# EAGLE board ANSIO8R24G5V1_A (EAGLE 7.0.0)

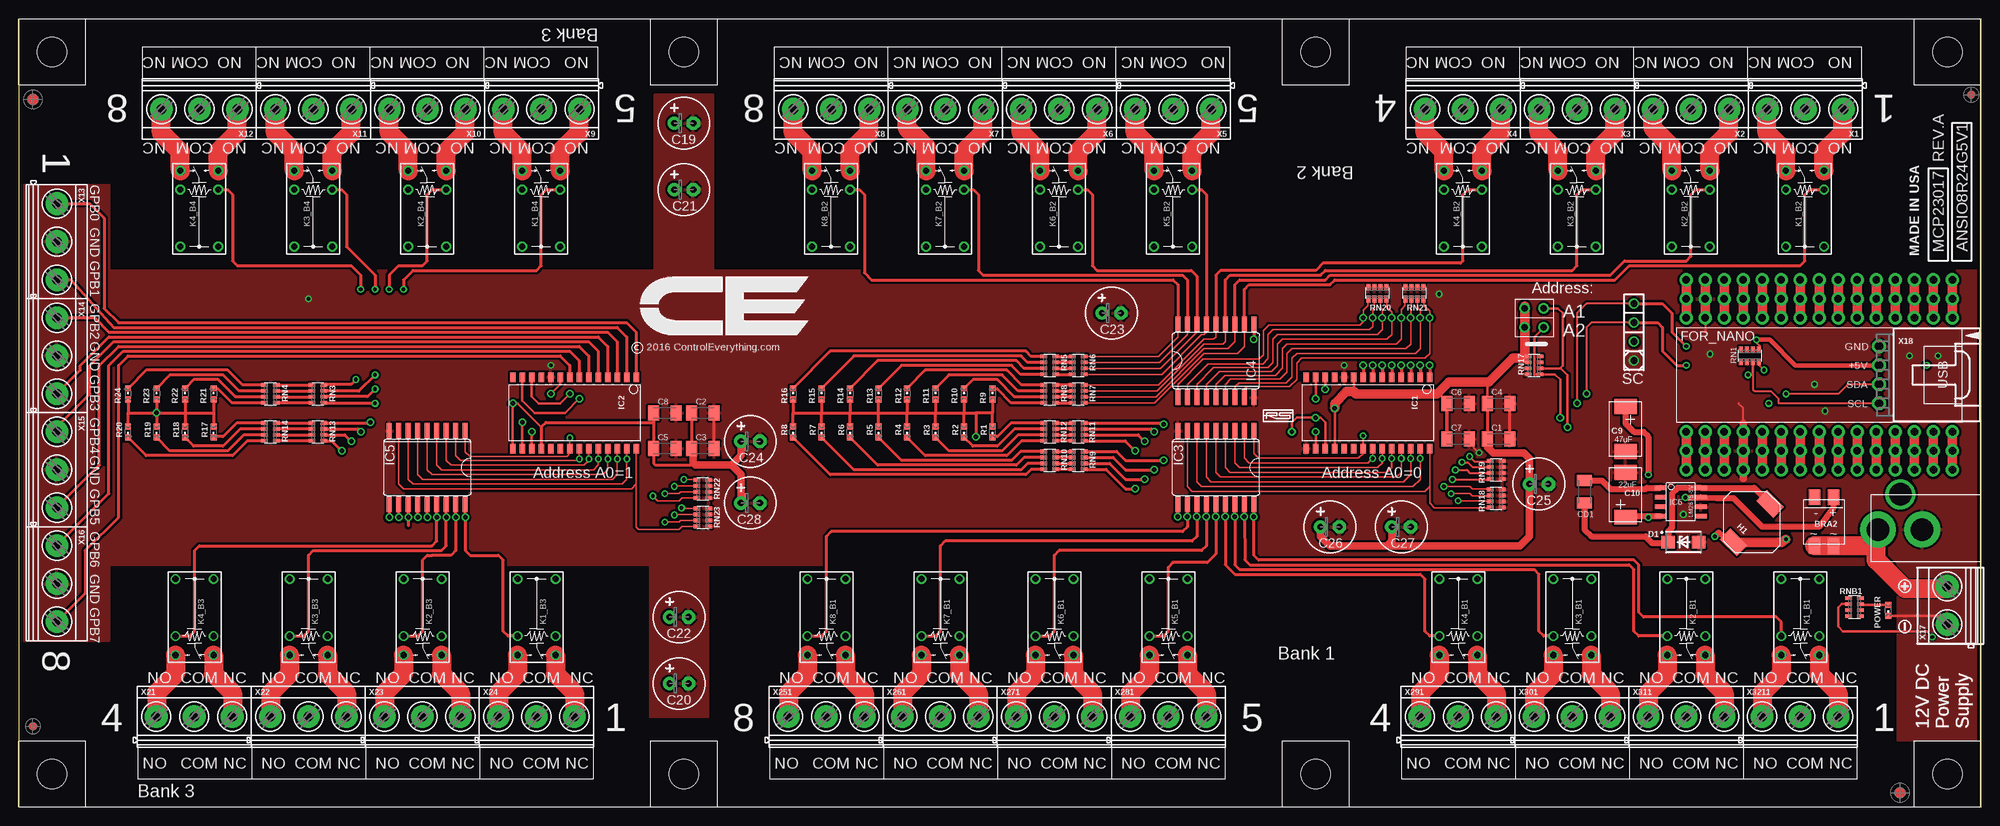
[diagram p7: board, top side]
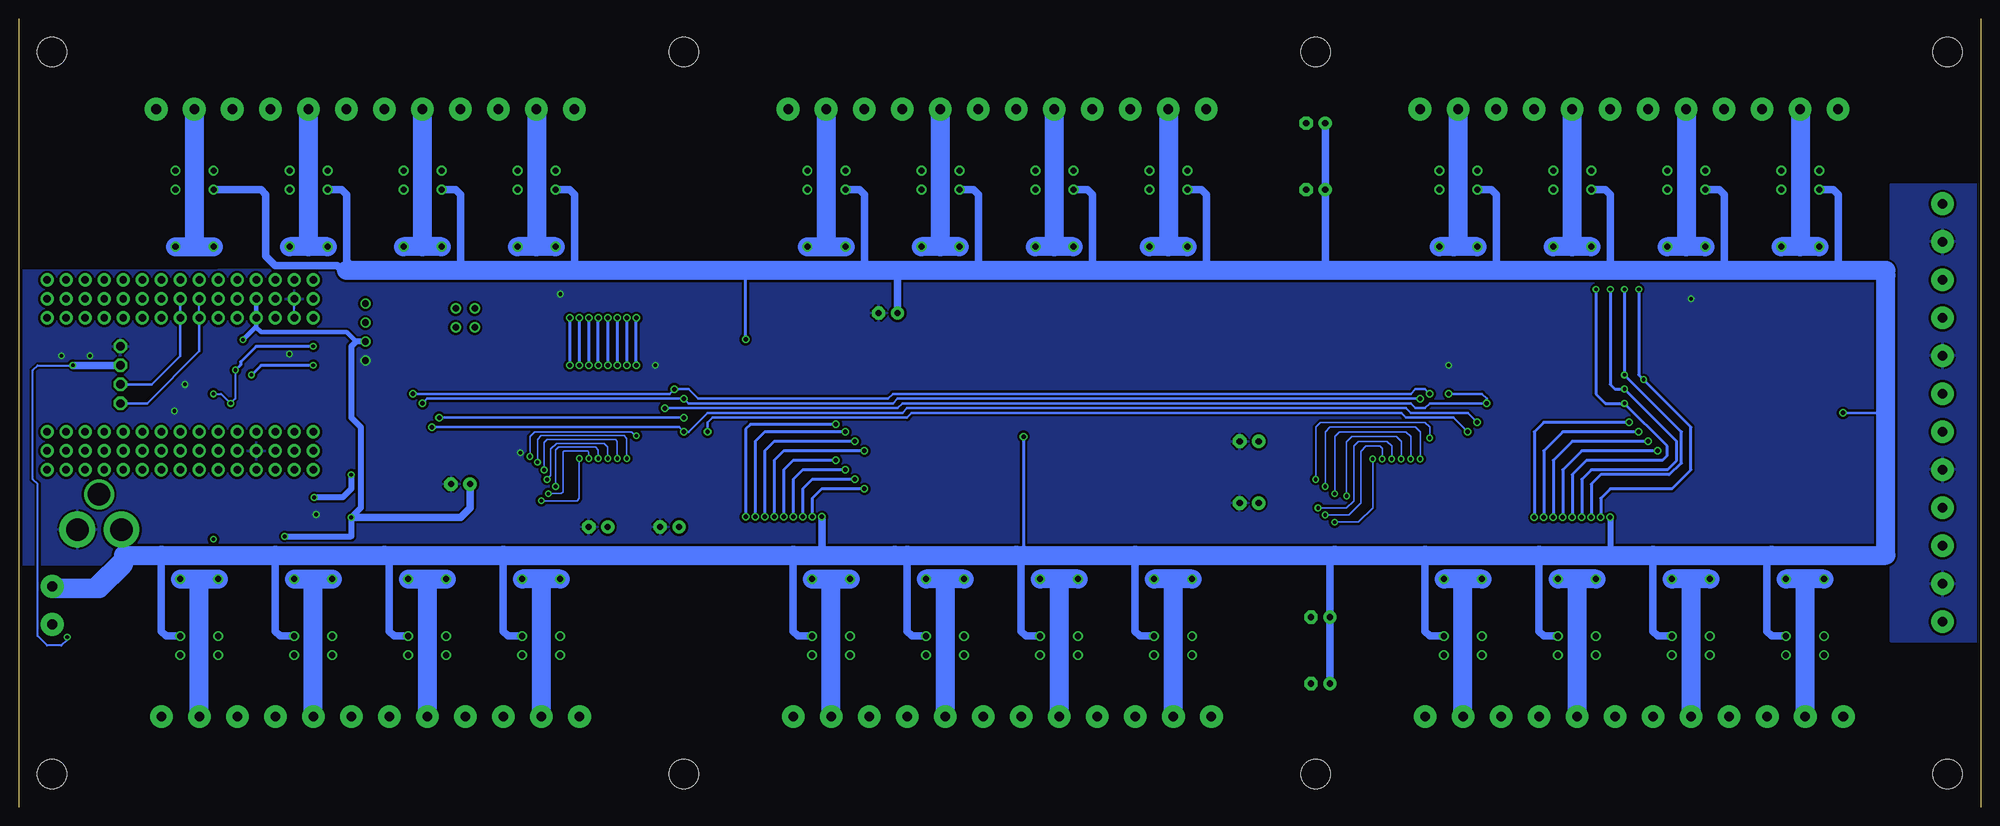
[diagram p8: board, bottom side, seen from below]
Size 262.25 x 105.42 mm. Coordinates in mm from the lower left corner, seen from the top.
Outline: 262.24,105.42 262.24,0
Outline: 0,105.42 0,0.01
Outline: 262.25,71.77 262.25,13.98
Copper layers (1*16): Top 0.035mm / dielectric 1.5mm / Bottom 0.035mm
Design rules "default *": minimum track width 6mil, minimum drill 12mil, track to track 5mil, track to pad 5mil, pad to pad 5mil, via to via 5mil, smd to smd 5mil, copper to edge 20mil, drill to drill 8mil, minimum pad ring 10mil, minimum via ring 8mil, stop-mask expansion 4mil, vias tented up to drill 0mil, thermal gap 10mil

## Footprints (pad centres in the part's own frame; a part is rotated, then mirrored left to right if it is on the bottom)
MB2S = smd 1.55 x 2.1: + 0,-6.5; - 2.54,-6.5; ~@1 0,0; ~@2 2.54,0
_CA_.1UF_50V = smd 1.5 x 2: 1 -1.5,0; 2 1.5,0
_CB_10UF_25V = smd 1.5 x 2: 1 -1.5,0; 2 1.5,0
C2917(7343)-Y = smd 2 x 3: 1 -3,0; 2 3,0
E-025X060 = drill 0.813 pad 1.778: + -1.27,0 | drill 0.813 pad 1.778 octagon: - 1.27,0
_CD_10NF_50V = smd 1.5 x 2: 1 -1.5,0; 2 1.5,0
DO214AC_ZENER = smd 1.8 x 1.7: A 2.05,0; C -2.05,0
ARDUINO_NANO = drill 1 pad 1.778: 3V1 -2.54,-2.54; 3V3 0,-2.54; 5V 0,-27.94; 5V1 -2.54,-27.94; A0 0,-7.62; A1 0,-10.16; A2 0,-12.7; A3 0,-15.24; A4 0,-17.78; A5 0,-20.32; A6 0,-22.86; A7 0,-25.4; A8 -2.54,-7.62; A9 -2.54,-10.16; A10 -2.54,-12.7; A11 -2.54,-15.24; A12 -2.54,-17.78; A13 -2.54,-20.32; A14 -2.54,-22.86; A15 -2.54,-25.4; D1 -2.54,0; D2 20.32,-25.4; D3 20.32,-22.86; D4 20.32,-20.32; D5 20.32,-17.78; D6 20.32,-15.24; D7 20.32,-12.7; D8 20.32,-10.16; D9 20.32,-7.62; D10 20.32,-5.08; D11 20.32,-2.54; D12 20.32,0; D13 0,0; D14 22.86,0; D15 22.86,-2.54; D16 22.86,-5.08; D17 22.86,-7.62; D18 22.86,-10.16; D19 22.86,-12.7; D20 22.86,-15.24; D21 22.86,-17.78; D22 22.86,-20.32; D23 22.86,-22.86; D24 22.86,-25.4; GND 0,-33.02; GND1 -2.54,-33.02; GND@1 20.32,-27.94; GND@2 22.86,-27.94; P$16 2.54,0; P$17 2.54,-2.54; P$18 2.54,-5.08; P$19 2.54,-7.62; P$20 2.54,-10.16; P$21 2.54,-12.7; P$22 2.54,-15.24; P$23 2.54,-17.78; P$24 2.54,-20.32; P$25 2.54,-22.86; P$26 2.54,-25.4; P$27 2.54,-27.94; P$28 2.54,-30.48; P$29 2.54,-33.02; P$30 2.54,-35.56; P$31 17.78,0; P$32 17.78,-2.54; P$33 17.78,-5.08; P$34 17.78,-7.62; P$35 17.78,-10.16; P$36 17.78,-12.7; P$37 17.78,-15.24; P$38 17.78,-17.78; P$39 17.78,-20.32; P$40 17.78,-22.86; P$41 17.78,-25.4; P$42 17.78,-27.94; P$43 17.78,-30.48; P$44 17.78,-33.02; P$45 17.78,-35.56; REF 0,-5.08; REF1 -2.54,-5.08; RST 0,-30.48; RST1 -2.54,-30.48; RST@1 20.32,-30.48; RST@2 22.86,-30.48; RX0 20.32,-33.02; RX1 22.86,-33.02; TX1 20.32,-35.56; TX2 22.86,-35.56; VIN 0,-35.56; VIN1 -2.54,-35.56
IND_ELL8TP = smd 2.054 x 3.2 rotated 45: 1 -2.442,-2.696; 2 2.442,2.442
SO28W = smd 0.762 x 1.27: 1 -7.62,-4.78; 2 -6.35,-4.78; 3 -5.08,-4.78; 4 -3.81,-4.78; 5 -2.54,-4.78; 6 -1.27,-4.78; 7 0,-4.78; 8 1.27,-4.78; 9 2.54,-4.78; 10 3.81,-4.78; 11 5.08,-4.78; 12 6.35,-4.78; 13 7.62,-4.78; 14 8.89,-4.78; 15 8.89,4.78; 16 7.62,4.78; 17 6.35,4.78; 18 5.08,4.78; 19 3.81,4.78; 20 2.54,4.78; 21 1.27,4.78; 22 0,4.78; 23 -1.27,4.78; 24 -2.54,4.78; 25 -3.81,4.78; 26 -5.08,4.78; 27 -6.35,4.78; 28 -7.62,4.78
SO18L = smd 0.66 x 2.032: 1 -5.08,-4.902; 2 -3.81,-4.902; 3 -2.54,-4.902; 4 -1.27,-4.902; 5 0,-4.902; 6 1.27,-4.902; 7 2.54,-4.902; 8 3.81,-4.902; 9 5.08,-4.902; 10 5.08,4.902; 11 3.81,4.902; 12 2.54,4.902; 13 1.27,4.902; 14 0,4.902; 15 -1.27,4.902; 16 -2.54,4.902; 17 -3.81,4.902; 18 -5.08,4.902
SO-8 = smd 0.6 x 1.55: 1 -1.905,-2.69; 2 -0.635,-2.69; 3 0.635,-2.69; 4 1.905,-2.69; 5 1.905,2.71; 6 0.635,2.71; 7 -0.635,2.71; 8 -1.905,2.71
G5V1 = drill 0.813: C1 -2.54,2.54; C2 -2.54,-2.54; COM@1 5.08,-2.54; COM@2 5.08,2.54; NC -5.08,-2.54; NO -5.08,2.54
CHIPLED_0603 = smd 0.8 x 0.8: A 0,-0.75; C 0,0.75
RND = smd 0.5 x 0.9: 1 -1.2,-0.8; 2 -0.4,-0.8; 3 0.4,-0.8; 4 1.2,-0.8; 5 1.2,0.8; 6 0.4,0.8; 7 -0.4,0.8; 8 -1.2,0.8
RNB = smd 0.5 x 0.9: 1 -1.2,-0.8; 2 -0.4,-0.8; 3 0.4,-0.8; 4 1.2,-0.8; 5 1.2,0.8; 6 0.4,0.8; 7 -0.4,0.8; 8 -1.2,0.8
RNE = smd 0.5 x 0.9: 1 -1.2,-0.8; 2 -0.4,-0.8; 3 0.4,-0.8; 4 1.2,-0.8; 5 1.2,0.8; 6 0.4,0.8; 7 -0.4,0.8; 8 -1.2,0.8
PCB_MOUNTING_HOLE = hole 3.962: 4.445,4.445
PJ-102A = drill 3 pad 4.8: RING 0.1,-3.39; TIP 0.1,-9.29 | drill 3 pad 3.251: RING_SW -4.6,-6.29
JUMPER_2X2 = drill 0.9: A1 0,2.54; A2 0,0; B1 2.54,2.54; B2 2.54,0
MKDSN1,5/3-5,08 = drill 1.3 pad 3.048: 1 -7.641,0.025; 2 -2.561,0.025; 3 2.519,0.025
MKDSN1,5/2-5,08 = drill 1.3 pad 3.048: 1 -2.561,0.025; 2 2.519,0.025
70553-04 = drill 1.1 pad 1.778 octagon: 1 -3.81,-7.62; 2 -1.27,-7.62; 3 1.27,-7.62; 4 3.81,-7.62

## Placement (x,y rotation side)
BRA2  MB2S_  [MB2S]  242.57,34.94 180 top
C1  [_CA_.1UF_50V]  197.8,49.22 0 top
C2  _CB_10UF_25VC1206K  [_CB_10UF_25V]  91.44,52.72 0 top
C3  [_CA_.1UF_50V]  91.44,47.95 0 top
C4  _CB_10UF_25VC1206K  [_CB_10UF_25V]  197.8,53.99 0 top
C5  [_CA_.1UF_50V]  86.36,47.95 0 top
C6  _CB_10UF_25VC1206K  [_CB_10UF_25V]  192.41,53.99 0 top
C7  [_CA_.1UF_50V]  192.41,49.22 0 top
C8  _CB_10UF_25VC1206K  [_CB_10UF_25V]  86.36,52.72 0 top
C9  47uF  [C2917(7343)-Y]  214.76,50.56 270 top
C10  22uF  [C2917(7343)-Y]  214.76,41.77 90 top
C19  100uF  [E-025X060]  88.9,91.45 0 top
C20  100uF  [E-025X060]  88.27,16.52 0 top
C21  100uF  [E-025X060]  88.9,82.56 0 top
C22  100uF  [E-025X060]  88.27,25.41 0 top
C23  100uF  [E-025X060]  146.05,66.05 0 top
C24  100uF  [E-025X060]  97.79,48.91 0 top
C25  100uF  [E-025X060]  203.2,43.19 0 top
C26  100uF  [E-025X060]  175.26,37.48 0 top
C27  100uF  [E-025X060]  184.78,37.48 0 top
C28  100uF  [E-025X060]  97.79,40.65 0 top
CD1  [_CD_10NF_50V]  209.3,42.18 270 top
D1  B360A  [DO214AC_ZENER]  222.5,35.45 0 top
FOR_NANO  ARDUINO_NANO  [ARDUINO_NANO]  258.44,67.96 270 top
H1  ELL8TP  [IND_ELL8TP]  231.65,38.11 0 top
IC1  MCP23017SO  [SO28W]  180.97,52.72 180 top
IC2  MCP23017SO  [SO28W]  74.93,52.72 180 top
IC3  ULN2803  [SO18L]  160.02,45.42 180 top
IC4  ULN2803  [SO18L]  160.02,59.7 0 top
IC5  ULN2803  [SO18L]  54.61,45.42 180 top
IC6  LM2675-5V  [SO-8]  222.12,40.78 270 top
K1_B1  G5V1  [G5V1]  238.12,25.41 90 top
K1_B2  G5V1  [G5V1]  238.76,80.02 270 top
K1_B3  G5V1  [G5V1]  69.22,25.41 90 top
K1_B4  G5V1  [G5V1]  69.85,80.02 270 top
K2_B1  G5V1  [G5V1]  222.88,25.41 90 top
K2_B2  G5V1  [G5V1]  223.52,80.02 270 top
K2_B3  G5V1  [G5V1]  53.98,25.41 90 top
K2_B4  G5V1  [G5V1]  54.61,80.02 270 top
K3_B1  G5V1  [G5V1]  207.65,25.41 90 top
K3_B2  G5V1  [G5V1]  208.28,80.02 270 top
K3_B3  G5V1  [G5V1]  38.73,25.41 90 top
K3_B4  G5V1  [G5V1]  39.37,80.02 270 top
K4_B1  G5V1  [G5V1]  192.41,25.41 90 top
K4_B2  G5V1  [G5V1]  193.04,80.02 270 top
K4_B3  G5V1  [G5V1]  23.5,25.41 90 top
K4_B4  G5V1  [G5V1]  24.13,80.02 270 top
K5_B1  G5V1  [G5V1]  153.67,25.41 90 top
K5_B2  G5V1  [G5V1]  154.31,80.02 270 top
K6_B1  G5V1  [G5V1]  138.43,25.41 90 top
K6_B2  G5V1  [G5V1]  139.06,80.02 270 top
K7_B1  G5V1  [G5V1]  123.19,25.41 90 top
K7_B2  G5V1  [G5V1]  123.83,80.02 270 top
K8_B1  G5V1  [G5V1]  107.95,25.41 90 top
K8_B2  G5V1  [G5V1]  108.58,80.02 270 top
POWER  LED_NCD  [CHIPLED_0603]  249.87,26.3 180 top
R1  LED_NCD  [CHIPLED_0603]  130.18,50.18 180 top
R2  LED_NCD  [CHIPLED_0603]  126.36,50.18 180 top
R3  LED_NCD  [CHIPLED_0603]  122.56,50.18 180 top
R4  LED_NCD  [CHIPLED_0603]  118.75,50.18 180 top
R5  LED_NCD  [CHIPLED_0603]  114.94,50.18 180 top
R6  LED_NCD  [CHIPLED_0603]  111.12,50.18 180 top
R7  LED_NCD  [CHIPLED_0603]  107.31,50.18 180 top
R8  LED_NCD  [CHIPLED_0603]  103.5,50.18 180 top
R9  LED_NCD  [CHIPLED_0603]  130.18,55.26 0 top
R10  LED_NCD  [CHIPLED_0603]  126.36,55.26 0 top
R11  LED_NCD  [CHIPLED_0603]  122.56,55.26 0 top
R12  LED_NCD  [CHIPLED_0603]  118.75,55.26 0 top
R13  LED_NCD  [CHIPLED_0603]  114.94,55.26 0 top
R14  LED_NCD  [CHIPLED_0603]  111.12,55.26 0 top
R15  LED_NCD  [CHIPLED_0603]  107.31,55.26 0 top
R16  LED_NCD  [CHIPLED_0603]  103.5,55.26 0 top
R17  LED_NCD  [CHIPLED_0603]  26.04,50.18 180 top
R18  LED_NCD  [CHIPLED_0603]  22.23,50.18 180 top
R19  LED_NCD  [CHIPLED_0603]  18.41,50.18 180 top
R20  LED_NCD  [CHIPLED_0603]  14.61,50.18 180 top
R21  LED_NCD  [CHIPLED_0603]  26.04,55.26 0 top
R22  LED_NCD  [CHIPLED_0603]  22.23,55.26 0 top
R23  LED_NCD  [CHIPLED_0603]  18.41,55.26 0 top
R24  LED_NCD  [CHIPLED_0603]  14.61,55.26 0 top
RN1  _RND_4.7K  [RND]  231.39,60.34 0 top
RN3  _RNB_510  [RNB]  40.01,55.26 270 top
RN4  _RNB_510  [RNB]  33.66,55.26 270 top
RN5  _RNB_510  [RNB]  137.79,59.07 270 top
RN6  _RNB_510  [RNB]  141.6,59.07 270 top
RN7  _RNB_510  [RNB]  141.6,55.26 270 top
RN8  _RNB_510  [RNB]  137.79,55.26 270 top
RN9  _RNB_510  [RNB]  141.6,46.37 270 top
RN10  _RNB_510  [RNB]  137.79,46.37 270 top
RN11  _RNB_510  [RNB]  141.6,50.18 90 top
RN12  _RNB_510  [RNB]  137.79,50.18 90 top
RN13  _RNB_510  [RNB]  40.01,50.18 270 top
RN14  _RNB_510  [RNB]  33.66,50.18 270 top
RN17  _RNE_10K  [RNE]  202.56,59.07 270 top
RN18  _RNE_10K  [RNE]  197.49,41.29 90 top
RN19  _RNE_10K  [RNE]  197.49,45.1 90 top
RN20  _RNE_10K  [RNE]  181.61,68.72 180 top
RN21  _RNE_10K  [RNE]  186.56,68.72 180 top
RN22  _RNE_10K  [RNE]  91.44,42.56 90 top
RN23  _RNE_10K  [RNE]  91.44,38.75 90 top
RNB1  _RNB_510  [RNB]  245.36,26.75 90 top
U$1  PCB_MOUNTING_HOLE  [PCB_MOUNTING_HOLE]  177.8,96.53 90 top
U$2  PCB_MOUNTING_HOLE  [PCB_MOUNTING_HOLE]  93.34,96.53 90 top
U$3  PCB_MOUNTING_HOLE  [PCB_MOUNTING_HOLE]  262.25,96.53 90 top
U$4  PCB_MOUNTING_HOLE  [PCB_MOUNTING_HOLE]  0,8.9 270 top
U$5  PCB_MOUNTING_HOLE  [PCB_MOUNTING_HOLE]  84.45,8.9 270 top
U$6  2.1MMJACK  [PJ-102A]  257.81,37.22 270 top
U$7  PCB_MOUNTING_HOLE  [PCB_MOUNTING_HOLE]  8.89,96.53 90 top
U$9  PCB_MOUNTING_HOLE  [PCB_MOUNTING_HOLE]  93.34,96.53 90 top
U$10  PCB_MOUNTING_HOLE  [PCB_MOUNTING_HOLE]  168.91,8.9 270 top
U$11  PCB_MOUNTING_HOLE  [PCB_MOUNTING_HOLE]  253.37,8.9 270 top
U$12  PCB_MOUNTING_HOLE  [PCB_MOUNTING_HOLE]  84.45,8.9 270 top
U$13  JUMPER_2X2  [JUMPER_2X2]  201.29,66.69 270 top
U$15  [VISION_REF15]  251.46,1.92 90 top
U$16  [ICON_MINUS]  252.09,24.14 90 top
U$17  [ICON_PLUS]  252.09,29.54 0 top
U$18  [VISION_REF10]  260.99,95.26 90 top
U$20  [ICON_MINUS]  252.09,24.14 90 top
U$21  [ICON_USA]  254,73.67 90 top
U$22  [ICON_MINUS]  252.09,24.14 90 top
U$23  [VISION_REF15]  1.91,94.63 90 top
U$24  [ICON_PLUS]  252.09,29.54 0 top
U$25  [ICON_PLUS]  252.09,29.54 0 top
U$28  [VISION_REF10]  1.91,10.81 90 top
X1  MKDSN1,5/3-5,08  [MKDSN1,5/3-5,08]  236.22,93.36 180 top
X2  MKDSN1,5/3-5,08  [MKDSN1,5/3-5,08]  220.98,93.36 180 top
X3  MKDSN1,5/3-5,08  [MKDSN1,5/3-5,08]  205.74,93.36 180 top
X4  MKDSN1,5/3-5,08  [MKDSN1,5/3-5,08]  190.5,93.36 180 top
X5  MKDSN1,5/3-5,08  [MKDSN1,5/3-5,08]  151.76,93.36 180 top
X6  MKDSN1,5/3-5,08  [MKDSN1,5/3-5,08]  136.53,93.36 180 top
X7  MKDSN1,5/3-5,08  [MKDSN1,5/3-5,08]  121.28,93.36 180 top
X8  MKDSN1,5/3-5,08  [MKDSN1,5/3-5,08]  106.05,93.36 180 top
X9  MKDSN1,5/3-5,08  [MKDSN1,5/3-5,08]  67.31,93.36 180 top
X10  MKDSN1,5/3-5,08  [MKDSN1,5/3-5,08]  52.07,93.36 180 top
X11  MKDSN1,5/3-5,08  [MKDSN1,5/3-5,08]  36.83,93.36 180 top
X12  MKDSN1,5/3-5,08  [MKDSN1,5/3-5,08]  21.59,93.36 180 top
X13  MKDSN1,5/3-5,08  [MKDSN1,5/3-5,08]  5.08,73.04 270 top
X14  MKDSN1,5/3-5,08  [MKDSN1,5/3-5,08]  5.08,57.8 270 top
X15  MKDSN1,5/3-5,08  [MKDSN1,5/3-5,08]  5.08,42.56 270 top
X16  MKDSN1,5/3-5,08  [MKDSN1,5/3-5,08]  5.08,27.32 270 top
X17  MKDSN1,5/2-5,08  [MKDSN1,5/2-5,08]  257.81,27 90 top
X18  C-GRID-04-70553  [70553-04]  256.29,57.8 270 top
X21  MKDSN1,5/3-5,08  [MKDSN1,5/3-5,08]  26.04,12.08 0 top
X22  MKDSN1,5/3-5,08  [MKDSN1,5/3-5,08]  41.27,12.08 0 top
X23  MKDSN1,5/3-5,08  [MKDSN1,5/3-5,08]  56.52,12.08 0 top
X24  MKDSN1,5/3-5,08  [MKDSN1,5/3-5,08]  71.75,12.08 0 top
X251  MKDSN1,5/3-5,08  [MKDSN1,5/3-5,08]  110.49,12.08 0 top
X261  MKDSN1,5/3-5,08  [MKDSN1,5/3-5,08]  125.73,12.08 0 top
X271  MKDSN1,5/3-5,08  [MKDSN1,5/3-5,08]  140.97,12.08 0 top
X281  MKDSN1,5/3-5,08  [MKDSN1,5/3-5,08]  156.21,12.08 0 top
X291  MKDSN1,5/3-5,08  [MKDSN1,5/3-5,08]  194.94,12.08 0 top
X301  MKDSN1,5/3-5,08  [MKDSN1,5/3-5,08]  210.19,12.08 0 top
X311  MKDSN1,5/3-5,08  [MKDSN1,5/3-5,08]  225.43,12.08 0 top
X3211  MKDSN1,5/3-5,08  [MKDSN1,5/3-5,08]  240.66,12.08 0 top

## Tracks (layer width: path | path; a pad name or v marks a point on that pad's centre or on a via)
GND  (via drill 0.5, 0.9)
  Top 0.254: 230.5,51.32 230.5,53.35 229.87,53.99 | FOR_NANO.GND@1 230.5,46.37 | 225.43,70.5 225.43,63.51
  Top 0.305: v195.2,47.38 193.68,48.91 193.68,49 C7.2 | POWER.C 256.67,25.55 X17.1
  Top 0.406: C1.2 C4.2 | C3.2 C2.2
  Top 1.016: X18.1 248.51,61.61 | 230.5,43.95 230.5,50.18 230.5,51.32
  Bottom 0.254: 225.43,65.42 FOR_NANO.GND
  other vias: 177.16,59.07 71.12,59.07 38.73,67.96 215.9,59.7 252.73,60.34 226.06,60.59 256.54,60.34 240.03,56.53 241.43,52.97 222.5,39.13 189.87,68.59
  pour Top (isolate 0.305): -1.91,32.4 -1.91,71.77 261.94,71.77 261.94,32.4
  pour Top (isolate 0.305): 261.94,20.33 251.14,20.33 251.14,32.4 261.94,32.4
  pour Bottom (isolate 0.305): -3.81,33.03 -3.81,72.4 262.25,71.77 262.25,32.4
  pour Top (isolate 0.305): -5.71,22.24 -5.71,83.2 12.06,83.2 12.06,22.24
  pour Bottom (isolate 0.305): -8.26,83.2 12.06,83.2 12.06,22.24 -8.26,22.24
  pour Top (isolate 0.305): 84.45,12.08 84.45,32.4 92.08,32.4 92.08,12.08
  pour Top (isolate 0.305): 92.71,71.77 85.09,71.77 85.09,95.26 92.71,95.26
  pour Top (isolate 0.305): 261.94,9.54 251.14,9.54 251.14,32.4 261.94,32.4
  pour Top: 261.94,8.9 251.14,8.9 251.14,32.4 261.94,32.4
GPB0
  Top 0.406: X13.1 9.5,80.68 11.43,78.75 11.43,66.69 13.34,64.78 81.28,64.78 82.55,63.51 IC2.1
GPB1
  Top 0.406: X13.3 6.96,70.52 12.7,64.15 80.01,64.15 81.28,62.88 IC2.2
GPB2
  Top 0.406: X14.1 10.18,65.44 12.06,63.51 78.74,63.51 80.01,62.24 IC2.3
GPB3
  Top 0.406: X14.3 8.26,58.43 8.26,59.07 12.06,62.88 77.47,62.88 78.74,61.61 IC2.4
GPB4
  Top 0.406: X15.1 5.11,50.84 9.53,55.26 9.53,59.07 12.7,62.24 76.2,62.24 77.47,60.97 IC2.5
GPB5
  Top 0.406: X15.3 10.79,45.73 10.79,59.07 13.34,61.61 74.93,61.61 76.2,60.34 IC2.6
GPB6
  Top 0.406: X16.1 12.06,41.92 12.06,59.07 13.97,60.97 73.66,60.97 74.93,59.7 IC2.7
GPB7
  Top 0.406: X16.3 8.89,28.58 8.89,34.3 13.34,38.75 13.34,59.07 14.61,60.34 72.39,60.34 73.66,59.07 IC2.8
I2C_SCL  (via drill 0.5, 0.6, 0.9)
  Top 0.254: v215.9,64.78 210.19,64.78 209.55,64.15 v209.55,55.26 | X18.4 235.2,53.99 235.2,54.62 234.44,55.38 234.2,55.62 234.19,55.64 232.03,55.64 231.79,55.87 RN1.3 231.78,59.52 231.78,57.8 v231.14,57.8
  Top 0.305: IC2.12 68.58,54.89 69.48,53.99 72.39,53.99 v73.66,55.26 | v174.62,55.89 IC1.12
  Top 0.406: v215.9,64.78 219.07,64.78 219.71,64.15 219.71,60.97 221.62,59.07 v222.88,59.07
  Bottom 0.254: 238.12,65.42 FOR_NANO.A5
  Bottom 0.305: v209.55,55.26 175.26,55.26 v174.62,55.89 172.72,55.89 171.45,54.62 146.05,54.62 145.41,55.26 76.2,55.26 75.56,55.89 74.3,55.89 v73.66,55.26 | 238.12,65.42 238.12,60.97 245.11,53.99 X18.4
  Bottom 0.406: v222.88,59.07 229.87,59.07 v231.14,57.8
I2C_SDA  (via drill 0.5, 0.6, 0.9)
  Top 0.254: v215.9,67.32 209.55,67.32 208.28,66.05 v208.28,53.99 | RN1.4 232.59,59.14 v233.3,58.43 | v233.93,53.98 v233.93,53.99 | X18.3 244.47,56.53 243.21,55.26 v236.22,55.26
  Top 0.305: IC2.13 67.31,54.37 68.97,52.72 73.03,52.72 v74.93,54.62 | v173.35,54.62 IC1.13
  Top 0.406: v215.9,67.32 219.71,67.32 220.98,66.05 220.98,63.51 v222.88,61.61
  Bottom 0.254: v233.3,58.43 233.3,54.62 v233.93,53.99 235.2,55.26 v236.22,55.26
  Bottom 0.305: v74.93,54.62 144.78,54.62 145.41,53.99 172.72,53.99 v173.35,54.62 207.65,54.62 v208.28,53.99 | FOR_NANO.A4 240.66,60.34 244.47,56.53 X18.3
  Bottom 0.406: v222.88,61.61 230.52,61.61 RN1.4 232.59,59.14 v233.3,58.43
N$1
  Bottom 2.54: K8_B2.COM@1 108.58,74.94 | 108.58,74.94 K8_B2.COM@2 | X8.2 108.61,74.96 108.58,74.94
N$2
  Top 2.54: K8_B2.NC 106.05,87.64 103.5,90.18 103.5,93.31 X8.3
N$3
  Top 2.54: K8_B2.NO 111.12,87.64 113.67,90.18 113.67,93.31 X8.1
N$4
  Top 2.54: K7_B2.NO 126.36,87.64 128.91,90.18 128.91,93.31 X7.1
N$5
  Top 2.54: K6_B2.NO 141.6,87.64 144.15,90.18 144.15,93.31 X6.1
N$6
  Top 2.54: K7_B2.NC 121.28,88.28 118.75,90.82 118.75,93.31 X7.3
N$7
  Bottom 2.54: K7_B2.COM@1 123.83,74.94 | 123.83,74.94 K7_B2.COM@2 | X7.2 123.85,74.96 123.83,74.94
N$8
  Top 2.54: K6_B2.NC 136.53,87.64 133.99,90.18 133.99,93.31 X6.3
N$10
  Top 2.54: K4_B2.NO 195.58,87.64 198.12,90.18 198.12,93.31 X4.1
N$11
  Top 2.54: K4_B2.NC 190.5,87.64 187.96,90.18 187.96,93.31 X4.3
N$12
  Bottom 2.54: K4_B2.COM@1 193.04,74.94 | 193.04,74.94 K4_B2.COM@2 | X4.2 193.06,74.96 193.04,74.94
N$14
  Bottom 2.54: K6_B2.COM@1 139.06,74.94 | 139.06,74.94 K6_B2.COM@2 | X6.2 139.09,74.96 139.06,74.94
N$31
  Bottom 2.54: 257.81,29.22 251.46,29.22 248.28,32.4
N$33
  Top 2.54: K5_B2.NC 151.76,87.64 149.22,90.18 149.22,93.31 X5.3
N$34
  Bottom 2.54: K5_B2.COM@2 154.31,74.94 | 154.31,74.94 K5_B2.COM@1 | X5.2 154.33,74.96 154.31,74.94
N$35
  Top 2.54: K5_B2.NO 156.84,87.64 159.38,90.18 159.38,93.31 X5.1
N$36
  Top 2.54: K3_B2.NO 210.82,87.64 213.36,90.18 213.36,93.31 X3.1
N$37
  Top 2.54: K3_B2.NC 205.74,87.64 203.2,90.18 203.2,93.31 X3.3
N$38
  Bottom 2.54: K3_B2.COM@1 208.28,74.94 | 208.28,74.94 K3_B2.COM@2 | X3.2 208.3,74.96 208.28,74.94
N$39
  Top 2.54: K2_B2.NO 226.06,87.64 228.6,90.18 228.6,93.31 X2.1
N$40
  Top 2.54: K2_B2.NC 220.98,88.28 218.44,90.82 218.44,93.31 X2.3
N$41
  Bottom 2.54: K2_B2.COM@1 223.52,74.94 | 223.52,74.94 K2_B2.COM@2 | X2.2 223.54,74.96 223.52,74.94
N$42
  Top 2.54: K1_B2.NO 241.3,87.64 243.84,90.18 243.84,93.31 X1.1
N$43
  Top 2.54: K1_B2.NC 236.22,87.64 233.68,90.18 233.68,93.31 X1.3
N$44
  Bottom 2.54: K1_B2.COM@2 238.76,74.94 | 238.76,74.94 K1_B2.COM@1 | X1.2 238.78,75.6 238.76,75.58 238.76,74.94
N$78
  Bottom 2.54: K1_B4.COM@1 70.48,74.94 | 70.48,74.94 K1_B4.COM@2 | X9.2 69.87,75.56 70.48,74.94
N$79
  Top 2.54: K1_B4.NC 67.31,87.64 64.77,90.18 64.77,93.31 X9.3
N$80
  Top 2.54: K1_B4.NO 72.39,87.64 74.93,90.18 74.93,93.31 X9.1
N$81
  Top 2.54: K2_B4.NO 57.15,87.64 59.69,90.18 59.69,93.31 X10.1
N$82
  Top 2.54: K3_B4.NO 41.91,87.64 44.45,90.18 44.45,93.31 X11.1
N$83
  Top 2.54: K2_B4.NC 52.07,87.64 49.53,90.18 49.53,93.31 X10.3
N$84
  Bottom 2.54: K2_B4.COM@1 54.61,74.94 | 54.61,74.94 K2_B4.COM@2 | X10.2 54.63,74.96 54.61,74.94
N$85
  Top 2.54: K3_B4.NC 36.83,87.64 34.29,90.18 34.29,93.31 X11.3
N$86
  Bottom 2.54: K3_B4.COM@1 39.37,74.94 | 39.37,74.94 K3_B4.COM@2 | X11.2 39.39,74.96 39.37,74.94
N$87
  Top 2.54: K4_B4.NC 21.59,87.64 19.05,90.18 19.05,93.31 X12.3
N$88
  Bottom 2.54: K4_B4.COM@1 24.13,74.94 | 24.13,74.94 K4_B4.COM@2 | X12.2 24.15,74.96 24.13,74.94
N$89
  Top 2.54: K4_B4.NO 26.67,87.64 29.21,90.18 29.21,93.31 X12.1
N$99
  Top 0.305: POWER.A 246.26,27.05 RNB1.3
N$100
  Top 0.813: 223.52,42.68 IC6.8 231.96,42.68 H1.2 | 223.52,42.68 221.74,42.68 220.98,41.92 220.98,37.38 220.47,36.87 220.47,35.46 D1.C 220.33,35.32 218.31,35.32 217.42,36.21 210.19,36.21 209.3,37.1 CD1.2 | 223.5,42.71 223.52,42.68
N$101
  Top 0.813: CD1.1 211.61,43.68 212.72,42.56 217.55,42.56 217.68,42.68 IC6.1
N$191
  Top 2.54: K4_B3.NO 20.95,17.79 18.41,15.25 18.41,12.12 X21.1
N$192
  Top 2.54: K4_B3.NC 26.04,17.79 28.57,15.25 28.57,12.12 X21.3
N$193
  Bottom 2.54: K4_B3.COM@2 23.5,30.49 | 23.5,30.49 K4_B3.COM@1 | X21.2 23.47,30.47 23.5,30.49
N$194
  Top 2.54: K3_B3.NO 36.2,17.79 33.66,15.25 33.66,12.12 X22.1
N$195
  Top 2.54: K3_B3.NC 41.27,17.79 43.81,15.25 43.81,12.12 X22.3
N$196
  Bottom 2.54: K3_B3.COM@2 38.73,30.49 | 38.73,30.49 K3_B3.COM@1 | X22.2 38.71,30.47 38.73,30.49
N$197
  Top 2.54: K2_B3.NO 51.44,17.79 48.9,15.25 48.9,12.12 X23.1
N$198
  Top 2.54: K2_B3.NC 56.52,17.79 59.05,15.25 59.05,12.12 X23.3
N$199
  Bottom 2.54: K2_B3.COM@2 53.98,30.49 | 53.98,30.49 K2_B3.COM@1 | X23.2 53.95,30.47 53.98,30.49
N$200
  Top 2.54: K1_B3.NO 66.67,17.79 64.14,15.25 64.14,12.12 X24.1
N$201
  Top 2.54: K1_B3.NC 71.75,17.79 74.3,15.25 74.3,12.12 X24.3
N$202
  Bottom 2.54: K1_B3.COM@2 69.85,30.49 | 69.85,30.49 K1_B3.COM@1 | X24.2 69.19,29.84 69.85,30.49
N$203
  Bottom 2.54: K8_B1.COM@2 107.95,30.49 | 107.95,30.49 K8_B1.COM@1 | X251.2 107.93,30.47 107.95,30.49
N$204
  Top 2.54: K8_B1.NC 110.49,17.79 113.03,15.25 113.03,12.12 X251.3
N$205
  Top 2.54: K8_B1.NO 105.41,17.79 102.87,15.25 102.87,12.12 X251.1
N$206
  Top 2.54: K7_B1.NO 120.65,17.79 118.11,15.25 118.11,12.12 X261.1
N$207
  Top 2.54: K6_B1.NO 135.89,17.79 133.35,15.25 133.35,12.12 X271.1
N$208
  Top 2.54: K7_B1.NC 125.73,17.79 128.27,15.25 128.27,12.12 X261.3
N$209
  Bottom 2.54: K7_B1.COM@2 123.83,30.49 | 123.83,30.49 K7_B1.COM@1 | X261.2 123.17,29.84 123.83,30.49
N$210
  Top 2.54: K6_B1.NC 140.97,17.79 143.51,15.25 143.51,12.12 X271.3
N$211
  Bottom 2.54: K6_B1.COM@2 137.79,30.49 | 137.79,30.49 K6_B1.COM@1 | X271.2 138.41,29.88 137.79,30.49
N$212
  Top 2.54: K5_B1.NC 156.21,17.79 158.75,15.25 158.75,12.12 X281.3
N$213
  Bottom 2.54: K5_B1.COM@1 153.67,30.49 | 153.67,30.49 K5_B1.COM@2 | X281.2 153.65,30.47 153.67,30.49
N$214
  Top 2.54: K5_B1.NO 151.13,17.79 148.59,15.25 148.59,12.12 X281.1
N$215
  Top 2.54: K4_B1.NO 189.87,17.79 187.32,15.25 187.32,12.12 X291.1
N$216
  Top 2.54: K4_B1.NC 194.94,17.79 197.49,15.25 197.49,12.12 X291.3
N$217
  Bottom 2.54: K4_B1.COM@2 192.41,30.49 | 192.41,30.49 K4_B1.COM@1 | X291.2 192.38,30.47 192.41,30.49
N$218
  Top 2.54: K3_B1.NO 205.1,17.79 202.56,15.25 202.56,12.12 X301.1
N$219
  Top 2.54: K3_B1.NC 210.19,17.79 212.72,15.25 212.72,12.12 X301.3
N$220
  Bottom 2.54: K3_B1.COM@1 207.65,30.49 | 207.65,30.49 K3_B1.COM@2 | X301.2 207.62,30.47 207.65,30.49
N$221
  Top 2.54: K2_B1.NO 220.34,17.79 217.81,15.25 217.81,12.12 X311.1
N$222
  Top 2.54: K2_B1.NC 225.43,17.79 227.97,15.25 227.97,12.12 X311.3
N$223
  Bottom 2.54: K2_B1.COM@1 222.88,30.49 | 222.88,30.49 K2_B1.COM@2 | X311.2 222.86,30.47 222.88,30.49
N$224
  Top 2.54: K1_B1.NO 235.59,17.79 233.04,15.25 233.04,12.12 X3211.1
N$225
  Top 2.54: K1_B1.NC 240.66,17.79 243.21,15.25 243.21,12.12 X3211.3
N$226
  Bottom 2.54: K1_B1.COM@1 238.12,30.49 | 238.12,30.49 K1_B1.COM@2 | X3211.2 238.1,30.47 238.12,30.49
N$405  (via drill 0.5)
  Top 0.229: IC1.21 179.71,47.32 179.07,46.68 165.74,46.68 165.1,47.32 IC3.1
  Top 0.254: 179.71,47.32 v179.71,49.67 | v193.93,46.88 194.56,46.24 196.63,46.24
  Top 0.305: 196.63,46.24 196.69,46.24 RN19.5
  Bottom 0.229: v179.71,49.67 179.71,49.54 180.34,50.18 193.29,50.18 193.93,49.54 v193.93,46.88
N$406  (via drill 0.5)
  Top 0.229: IC1.25 v184.79,46.62 184.78,44.78 184.15,44.14 160.66,44.14 160.02,44.78 IC3.5 | v190.5,42.88 193.99,42.88 194.31,42.56 196.62,42.56 RN18.5
  Bottom 0.229: v184.79,46.62 184.78,47.79 185.14,48.15 190.1,48.15 190.51,47.74 v190.5,42.88
N$407  (via drill 0.5)
  Top 0.229: IC1.26 v186.06,46.62 186.06,44.46 185.1,43.51 159.38,43.51 158.75,44.14 IC3.6 | v191.45,41.92 193.99,41.92 194.31,41.6 196.6,41.6 RN18.6
  Bottom 0.229: v186.06,46.62 186.06,47.51 186.18,47.64 189.36,47.64 189.48,47.51 189.48,42.18 189.74,41.92 v191.45,41.92
N$408  (via drill 0.6)
  Top 0.305: IC2.16 v67.31,51.45 | v173.35,50.18 IC1.16 | RN17.6 205.97,58.67 | 205.97,58.67 206.38,59.07 206.38,66.05 205.74,66.69 U$13.A1 | 205.97,58.67 206.14,58.67 207.01,57.8 v207.01,50.81
  Bottom 0.305: v67.31,51.45 68.58,52.72 76.2,52.72 76.83,53.35 143.51,53.35 144.15,52.72 170.18,52.72 172.72,50.18 v173.35,50.18 173.99,50.81 v207.01,50.81
N$409  (via drill 0.5)
  Top 0.229: IC1.22 180.97,46.68 180.34,46.05 164.47,46.05 163.83,46.68 IC3.2
  Top 0.254: 180.97,46.68 v180.97,46.62 | v192.91,46.11 193.68,46.11 194.31,45.48 196.67,45.48 RN19.6
  Bottom 0.229: v180.97,46.62 180.97,49.29 181.36,49.67 192.41,49.67 192.91,49.16 v192.91,46.11
N$410  (via drill 0.5)
  Top 0.229: IC1.23 182.25,46.05 181.61,45.42 163.19,45.42 162.56,46.05 IC3.3
  Top 0.254: 182.25,46.05 v182.25,46.62 | v192.02,45.1 193.55,45.1 193.93,44.72 196.67,44.72 RN19.7
  Bottom 0.229: v182.25,46.62 182.25,48.91 182.5,49.16 191.64,49.16 192.02,48.78 v192.02,45.1
  Bottom 0.254: 192.28,44.97 v192.02,45.1
N$411  (via drill 0.5)
  Top 0.229: IC1.24 183.51,45.42 182.88,44.78 161.93,44.78 161.29,45.42 IC3.4
  Top 0.254: 183.51,45.42 v183.51,46.62 | v191.64,43.83 196.62,43.83 RN19.8
  Bottom 0.229: v183.51,46.62 183.51,48.15 184.02,48.65 190.37,48.65 191.13,47.89 191.13,44.34 v191.64,43.83
N$416  (via drill 0.6)
  Top 0.203: 163.83,55.89 164.15,56.21 169.86,56.21 170.81,57.16 170.81,59.38 171.45,60.02 187.96,60.02 188.59,60.66 v188.59,65.42
  Top 0.229: v188.59,65.42 188.59,66.31 187.83,67.07 187.83,67.85 RN21.8
  Top 0.406: v188.59,59.07 IC1.1 | IC4.8 163.83,55.89
  Bottom 0.406: v188.59,65.42 v188.59,59.07
N$417  (via drill 0.6)
  Top 0.203: IC4.7 162.56,56.21 163.07,56.72 169.35,56.72 170.18,57.54 170.18,60.02 170.81,60.66 186.69,60.66 187.32,61.29 v187.32,65.42
  Top 0.229: v187.32,65.42 187.32,66.43 186.94,66.81 186.94,67.9 RN21.7
  Top 0.406: v187.32,59.07 IC1.2
  Bottom 0.406: v187.32,65.42 v187.32,59.07
N$418  (via drill 0.6)
  Top 0.203: IC4.6 161.29,56.53 161.99,57.23 168.59,57.23 169.54,58.18 169.54,60.66 170.18,61.29 185.42,61.29 186.06,61.93 v186.06,65.42
  Top 0.229: v186.06,65.42 186.06,66.94 186.18,67.07 186.18,67.9 RN21.6
  Top 0.406: v186.06,59.07 IC1.3
  Bottom 0.406: v186.06,65.42 v186.06,59.07
N$419  (via drill 0.6)
  Top 0.203: IC4.5 160.02,56.53 161.23,57.73 167.96,57.73 168.91,58.69 168.91,61.29 169.54,61.93 184.15,61.93 184.78,62.56 v184.78,65.42
  Top 0.229: v184.78,65.42 184.78,66.56 185.29,67.07 185.29,67.85 RN21.5
  Top 0.406: v184.78,59.07 IC1.4
  Bottom 0.406: v184.78,59.07 v184.78,65.42
N$420  (via drill 0.6)
  Top 0.203: IC4.4 158.75,56.53 160.46,58.24 167.45,58.24 168.28,59.07 168.28,61.93 168.91,62.56 182.88,62.56 183.51,63.19 v183.51,65.42
  Top 0.229: v183.51,65.42 183.51,66.18 182.88,66.81 182.88,67.85 RN20.8
  Top 0.406: v183.51,59.07 IC1.5
  Bottom 0.406: v183.51,65.42 v183.51,59.07
N$421  (via drill 0.6)
  Top 0.203: IC4.3 157.48,56.53 159.7,58.75 166.94,58.75 167.64,59.45 167.64,62.56 168.28,63.19 181.61,63.19 182.25,63.83 v182.25,65.42
  Top 0.229: v182.25,65.42 182.25,66.56 181.99,66.81 181.99,67.9 RN20.7
  Top 0.406: v182.25,59.07 IC1.6
  Bottom 0.406: v182.25,65.42 v182.25,59.07
N$422  (via drill 0.6)
  Top 0.203: IC4.2 156.21,56.53 158.94,59.26 166.31,59.26 167,59.96 167,63.19 167.64,63.83 180.53,63.83 180.97,64.28 v180.97,65.42
  Top 0.229: IC1.7 180.97,57.16 | v180.97,65.42 180.97,66.43 181.23,66.69 181.23,67.9 RN20.6
  Top 0.406: 180.97,65.05 v180.97,65.42 | v180.97,59.07 IC1.7
  Bottom 0.406: v180.97,65.42 v180.97,59.07
N$423  (via drill 0.6)
  Top 0.203: IC4.1 154.94,56.53 158.31,59.89 165.8,59.89 166.37,60.46 166.37,63.76 167.08,64.47 179.26,64.47 179.71,64.91 v179.71,65.42
  Top 0.229: v179.71,65.42 179.71,66.43 180.34,67.07 180.34,67.85 RN20.5
  Top 0.406: v179.71,59.07 IC1.8
  Bottom 0.406: v179.71,59.07 v179.71,65.42
N$424  (via drill 0.5)
  Top 0.229: IC2.21 v73.66,49.35 73.66,47.26 73.27,46.88 60.33,46.88 59.69,47.51 IC5.1 | v88.9,43.83 90.57,43.83 RN22.5
  Bottom 0.229: v73.66,49.35 73.66,50.81 74.3,51.45 88.27,51.45 88.9,50.81 v88.9,43.83
N$425  (via drill 0.5)
  Top 0.229: IC5.2 58.42,47 59.05,46.37 74.93,46.37 v74.93,46.56 IC2.22 | RN22.6 87.71,42.96 v87.63,42.88
  Bottom 0.229: v87.63,42.88 87.63,50.18 87,50.81 75.56,50.81 74.93,50.18 v74.93,46.56
N$426  (via drill 0.5)
  Top 0.229: IC5.3 57.15,46.37 57.78,45.73 75.56,45.73 76.2,46.37 v76.2,46.56 IC2.23 | RN22.7 88.5,42.16 88.27,41.92 v86.36,41.92
  Bottom 0.229: v86.36,41.92 86.36,49.54 85.72,50.18 76.83,50.18 76.2,49.54 v76.2,46.56
N$427  (via drill 0.5)
  Top 0.229: IC5.4 55.88,45.73 56.52,45.1 76.83,45.1 77.47,45.73 v77.47,46.56 IC2.24 | RN22.8 88.65,41.36 88.27,40.97 85.41,40.97 v84.77,41.6
  Bottom 0.229: v84.77,41.6 84.77,48.83 84.06,49.54 78.11,49.54 77.47,48.91 v77.47,46.56
N$428  (via drill 0.5)
  Top 0.229: IC5.5 54.61,45.1 55.24,44.46 78.11,44.46 78.74,45.1 v78.74,46.56 IC2.25 | RN23.5 88.65,39.95 v88.58,40.02
  Bottom 0.229: v88.58,40.02 84.77,40.02 83.82,40.97 83.82,48.27 83.19,48.91 79.38,48.91 78.74,48.27 v78.74,46.56
N$429  (via drill 0.5)
  Top 0.229: IC5.6 53.34,44.46 53.98,43.83 79.38,43.83 80.01,44.46 v80.01,46.56 IC2.26 | RN23.6 87.71,39.15 v87.63,39.07
  Bottom 0.229: v87.63,39.07 84.45,39.07 82.87,40.65 82.87,47.56 82.16,48.27 80.34,48.27 IC2.26 v80.01,46.56
N$430  (via drill 0.5)
  Top 0.229: IC5.7 52.07,43.83 52.7,43.19 80.64,43.19 81.28,43.83 v81.28,46.56 IC2.27 | RN23.7 88.5,38.35 88.27,38.11 v86.36,38.11
  Bottom 0.229: v86.36,38.11 83.19,38.11 81.28,40.02 v81.28,46.56
N$431
  Top 0.229: IC2.28 82.55,43.19 | 82.55,43.19 81.92,42.56 51.44,42.56 50.8,43.19 IC5.8 | RN23.8 88.65,37.55 88.27,37.16 82.87,37.16 82.55,37.48 82.55,43.19
N$441
  Top 0.406: RN5.1 135.32,60.27 134.62,60.97 108.47,60.97 R16.C
N$442
  Top 0.406: RN8.7 RN7.2
N$443
  Top 0.406: RN7.3 RN8.6
N$444
  Top 0.406: RN8.5 RN7.4
N$445
  Top 0.406: RN5.2 134.85,59.47 133.99,60.34 111.64,60.34 R15.C
N$446
  Top 0.406: RN4.3 28.98,54.86 26.67,57.16 23.38,57.16 R22.C
N$447
  Top 0.406: RN5.4 133.91,57.87 132.72,59.07 118,59.07 R13.C
N$448
  Top 0.406: RN5.5 RN6.4
N$449
  Top 0.406: RN7.1 RN8.8
N$450
  Top 0.406: RN8.1 134.06,56.46 132.08,58.43 121.17,58.43 R12.C
N$451
  Top 0.406: RN5.6 RN6.3
N$452
  Top 0.406: RN8.2 133.59,55.66 131.44,57.8 124.34,57.8 R11.C
N$453
  Top 0.406: RN6.2 RN5.7
N$454
  Top 0.406: RN5.8 RN6.1
N$455
  Top 0.406: RN3.4 RN4.5
N$458
  Top 0.406: RN5.3 134.38,58.67 133.35,59.7 114.82,59.7 R14.C
N$459
  Top 0.406: RN8.3 133.12,54.86 130.81,57.16 127.52,57.16 R10.C
N$461
  Top 0.406: RN4.1 29.91,56.46 27.94,58.43 17.03,58.43 R24.C
N$462
  Top 0.406: RN4.2 29.45,55.66 27.3,57.8 20.2,57.8 R23.C
N$463
  Top 0.406: RN12.4 RN11.5
N$464
  Top 0.406: RN4.4 28.5,54.06 26.67,55.89 26.15,55.89 R21.C
N$470
  Top 0.406: RN8.4 132.65,54.06 130.81,55.89 130.29,55.89 R9.C
N$473
  Top 0.406: RN12.5 132.65,51.38 130.81,49.54 130.29,49.54 R1.C
N$474
  Top 0.406: RN11.6 RN12.3
N$475
  Top 0.406: RN12.6 133.12,50.58 130.81,48.27 127.52,48.27 R2.C
N$476
  Top 0.406: RN12.7 133.59,49.78 131.44,47.64 124.34,47.64 R3.C
N$477
  Top 0.406: RN9.4 RN10.5
N$478
  Top 0.406: RN10.6 RN9.3
N$479
  Top 0.406: RN9.2 RN10.7
N$480
  Top 0.406: RN10.8 RN9.1
N$481
  Top 0.406: RN12.2 RN11.7
N$482
  Top 0.406: RN10.1 133.91,47.57 132.72,46.37 118,46.37 R5.C
N$483
  Top 0.406: RN12.8 134.06,48.98 132.08,47 121.17,47 R4.C
N$484
  Top 0.406: RN10.3 134.85,45.97 133.99,45.1 111.64,45.1 R7.C
N$485
  Top 0.406: RN10.4 135.32,45.17 134.62,44.46 108.47,44.46 R8.C
N$486
  Top 0.406: RN10.2 134.38,46.77 133.35,45.73 114.82,45.73 R6.C
N$487
  Top 0.406: RN14.3 30.08,49.78 27.94,47.64 20.2,47.64 R19.C
N$488
  Top 0.406: RN14.2 29.61,50.58 27.3,48.27 23.38,48.27 R18.C
N$489
  Top 0.406: RN14.1 29.14,51.38 27.3,49.54 26.15,49.54 R17.C
N$494
  Top 0.406: RN14.4 30.55,48.98 28.57,47 17.03,47 R20.C
N$498  (via drill 0.6)
  Top 0.305: IC2.17 v68.58,50.18 | v170.18,50.18 170.18,51.45 170.81,52.08 v173.35,52.08 173.99,52.08 174.62,51.45 IC1.17 | U$13.B1 202.56,62.88 202.56,57.8 202.63,57.87 RN17.5 205.35,57.87 206.06,57.16 v206.06,52.08
  Bottom 0.305: v68.58,50.18 70.48,52.08 76.83,52.08 77.47,52.72 142.94,52.72 143.51,52.08 169.54,52.08 170.18,51.45 v170.18,50.18 | v173.35,52.08 v206.06,52.08
N$500
  Top 0.406: RN11.8 RN12.1
N$501
  Top 0.406: RN13.4 RN14.5
N$502
  Top 0.406: RN14.6 RN13.3
N$503
  Top 0.406: RN13.2 RN14.7
N$504
  Top 0.406: RN14.8 RN13.1
N$505
  Top 0.406: RN4.6 RN3.3
N$506
  Top 0.406: RN4.7 RN3.2
N$507
  Top 0.406: RN4.8 RN3.1
N$525  (via drill 0.5)
  Top 0.229: IC3.7 157.48,43.51 158.12,42.88 186.37,42.88 187.32,43.83 v187.32,46.62 IC1.27 | v192.41,40.97 196.13,40.97 RN18.7
  Bottom 0.229: v192.41,40.97 187.64,40.97 187.32,41.29 v187.32,46.62
N$526
  Top 0.229: IC1.28 188.59,42.88 | 188.59,42.88 187.96,42.24 156.84,42.24 156.21,42.88 IC3.8 | 188.59,42.88 188.59,40.65 189.23,40.02 196.62,40.02 RN18.8
OC_R1_A  (via drill 0.6)
  Top 0.406: IC3.18 v165.1,38.81 165.07,38.46 165.1,38.11 165.1,33.67 165.74,33.03 215.9,33.03 216.53,32.4 216.53,26.05 217.17,25.41 234.95,25.41 235.59,24.78 K1_B1.C1 | RN11.4 152.97,51.38 v153.03,51.19
  Bottom 0.406: v153.03,51.19 164.47,51.19 165.1,50.56 v165.1,38.81
OC_R1_B
  Top 0.203: RN7.5 151.84,54.06 158.43,60.66 162.88,60.66 163.83,61.61 IC4.11
  Top 0.406: IC4.11 163.83,69.23 164.47,69.86 175.26,69.86 175.9,70.5 213.36,70.5 215.26,72.4 238.12,72.4 238.76,73.04 238.76,81.93 239.4,82.56 K1_B2.C1
OC_R1_C  (via drill 0.6)
  Top 0.406: RN13.8 46.92,51.38 v46.99,51.45 | IC5.18 v59.69,38.75 59.69,34.3 60.33,33.67 64.14,33.67 64.77,33.03 64.77,23.51 65.41,22.87 K1_B3.C1
  Bottom 0.406: v46.99,51.45 58.42,51.45 59.69,50.18 v59.69,38.75
OC_R2_A  (via drill 0.6)
  Top 0.406: RN11.3 151.37,50.58 v151.76,50.18 | IC3.17 v163.83,38.81 163.87,33.06 164.56,32.4 215.26,32.4 215.9,31.76 215.9,23.51 216.53,22.87 K2_B1.C1
  Bottom 0.406: v151.76,50.18 162.56,50.18 163.83,48.91 v163.83,38.81
OC_R2_B
  Top 0.203: IC4.12 162.56,62.24 161.61,61.29 158.43,61.29 152,54.86 RN7.6
  Top 0.406: IC4.12 162.56,69.86 163.19,70.5 174.62,70.5 175.26,71.13 212.72,71.13 214.63,73.04 222.88,73.04 223.52,73.67 223.52,81.93 224.16,82.56 K2_B2.C1
OC_R2_C  (via drill 0.6)
  Top 0.406: RN13.7 45.32,50.58 v45.72,50.18 | IC5.17 v58.42,38.75 58.42,34.3 57.78,33.67 55.88,33.67 55.24,33.67 54.61,33.67 53.98,33.03 53.98,23.51 53.34,22.87 K2_B3.C1
  Bottom 0.406: v45.72,50.18 55.88,50.18 58.42,47.64 v58.42,38.75
OC_R3_A  (via drill 0.6)
  Top 0.406: RN11.2 149.62,49.78 v150.5,48.91 | IC3.16 v162.56,38.81 162.56,32.4 163.19,31.76 202.56,31.76 203.2,31.13 203.2,23.51 203.84,22.87 K3_B1.C1
  Bottom 0.406: v150.5,48.91 161.29,48.91 162.56,47.64 v162.56,38.81
OC_R3_B
  Top 0.203: RN7.7 152.16,55.66 158.43,61.93 160.97,61.93 161.29,62.24 IC4.13
  Top 0.406: IC4.13 161.29,70.5 161.93,71.13 173.99,71.13 174.62,71.77 207.65,71.77 208.28,72.4 208.28,81.93 208.91,82.56 K3_B2.C1
OC_R3_C  (via drill 0.6)
  Top 0.406: RN13.6 43.58,49.78 v44.45,48.91 | IC5.16 v57.15,38.75 57.15,34.94 56.52,34.3 39.37,34.3 38.73,33.67 38.73,23.51 38.1,22.87 K3_B3.C1
  Bottom 0.406: v44.45,48.91 54.61,48.91 57.15,46.37 v57.15,38.75
OC_R4_A  (via drill 0.6)
  Top 0.406: RN11.1 147.88,48.98 v149.22,47.64 | IC3.15 v161.29,38.81 161.29,32.4 162.56,31.13 187.32,31.13 187.96,30.49 187.96,23.51 188.59,22.87 K4_B1.C1
  Bottom 0.406: v149.22,47.64 160.02,47.64 161.29,46.37 v161.29,38.81
OC_R4_B
  Top 0.203: RN7.8 152.33,56.46 158.43,62.56 159.7,62.56 160.02,62.88 IC4.14
  Top 0.406: IC4.14 160.02,71.13 160.66,71.77 173.35,71.77 174.31,72.72 192.72,72.72 193.04,73.04 193.04,81.93 193.68,82.56 K4_B2.C1
OC_R4_C  (via drill 0.6)
  Top 0.406: RN13.5 41.84,48.98 v43.18,47.64 | IC5.15 v55.88,38.75 55.88,35.57 55.24,34.94 24.13,34.94 23.5,34.3 23.5,23.51 22.86,22.87 K4_B3.C1
  Bottom 0.406: v43.18,47.64 53.34,47.64 55.88,45.1 v55.88,38.75
OC_R5_A  (via drill 0.6)
  Top 0.406: 154.31,32.71 158.88,32.71 160.02,33.86 v160.02,38.81 IC3.14 | 154.31,32.71 154.18,32.71 | RN9.8 146.75,47.57 147.96,46.37 v153.03,46.37 | K5_B1.C1 153.03,22.87 153.67,23.51 153.67,32.08 154.31,32.71
  Bottom 0.406: v153.03,46.37 158.75,46.37 160.02,45.1 v160.02,38.81
OC_R5_B
  Top 0.203: IC4.15 158.75,63.51 158.43,63.19 158.12,63.19 152.79,57.87 RN6.5
  Top 0.406: K5_B2.C1 158.12,82.56 158.75,81.93 IC4.15
OC_R5_C  (via drill 0.5, 0.6)
  Top 0.406: v54.61,38.75 IC5.14 | v47.62,53.99 40.88,53.99 RN3.5 | v51.44,69.23 51.44,70.5 52.7,71.77 69.22,71.77 69.85,72.4 69.85,81.93 70.48,82.56 K1_B4.C1
  Bottom 0.406: v54.61,38.75 54.61,44.46 52.7,46.37 42.55,46.37 41.91,47 41.91,48.27 v47.62,53.99 50.16,53.99 51.44,55.26 v51.44,69.23
OC_R6_A  (via drill 0.6)
  Top 0.406: RN9.7 146.28,46.77 147.96,45.1 v151.76,45.1 | IC3.13 v158.75,38.81 158.75,34.94 158.12,34.3 139.06,34.3 138.43,33.67 138.43,23.51 137.79,22.87 K6_B1.C1
  Bottom 0.406: v151.76,45.1 157.48,45.1 158.75,43.83 v158.75,38.81
OC_R6_B
  Top 0.203: RN6.6 152.63,58.67 157.48,63.51 IC4.16
  Top 0.406: IC4.16 157.48,71.01 156.72,71.77 144.15,71.77 143.51,72.4 143.51,81.93 142.88,82.56 K6_B2.C1
OC_R6_C  (via drill 0.5, 0.6)
  Top 0.406: v53.34,38.75 IC5.13 | v47.62,55.89 46.61,54.88 40.82,54.88 RN3.6 | v49.53,69.23 49.53,71.13 50.8,72.4 53.98,72.4 54.61,73.04 54.61,81.93 55.24,82.56 K2_B4.C1
  Bottom 0.406: v53.34,38.75 53.34,43.83 52.07,45.1 41.91,45.1 40.64,46.37 40.64,48.91 v47.62,55.89 48.9,55.89 49.53,56.53 v49.53,69.23
OC_R7_A  (via drill 0.6)
  Top 0.406: RN9.6 145.81,45.97 147.96,43.83 v150.5,43.83 | IC3.12 v157.48,38.81 157.48,36.21 156.84,35.57 123.83,35.57 123.19,34.94 123.19,23.51 122.56,22.87 K7_B1.C1
  Bottom 0.406: v150.5,43.83 156.21,43.83 157.48,42.56 v157.48,38.81
OC_R7_B
  Top 0.203: RN6.7 152.48,59.47 156.21,63.19 IC4.17
  Top 0.406: IC4.17 156.21,70.5 155.57,71.13 128.91,71.13 128.27,71.77 128.27,81.93 127.64,82.56 K7_B2.C1
OC_R7_C  (via drill 0.5, 0.6)
  Top 0.406: 52.07,37.61 IC5.12 v52.07,38.75 | v47.62,57.8 45.47,55.64 40.82,55.64 RN3.7 | v47.62,69.23 47.62,71.13 43.81,74.94 43.81,81.93 43.18,82.56 K3_B4.C1
  Bottom 0.406: v52.07,38.75 52.07,43.19 50.8,44.46 41.66,44.46 40.01,45.99 40.01,50.18 v47.62,57.8 v47.62,69.23
OC_R8_A  (via drill 0.6)
  Top 0.406: RN9.5 145.34,45.17 147.96,42.56 v149.22,42.56 | IC3.11 v156.21,38.81 156.21,37.48 155.57,36.84 108.58,36.84 107.95,36.21 107.95,23.51 107.31,22.87 K8_B1.C1
  Bottom 0.406: v149.22,42.56 154.94,42.56 156.21,41.29 v156.21,38.81
OC_R8_B
  Top 0.203: RN6.8 152.33,60.27 154.94,62.88 IC4.18
  Top 0.406: IC4.18 154.94,69.86 154.31,70.5 113.98,70.5 113.03,71.45 113.03,81.93 112.39,82.56 K8_B2.C1
OC_R8_C  (via drill 0.5, 0.6)
  Top 0.406: v50.8,38.75 IC5.11 | v45.09,57.16 44.45,56.53 40.88,56.53 RN3.8 | v45.72,69.23 45.72,71.13 44.77,72.08 44.45,72.4 29.21,72.4 28.57,73.04 28.57,81.93 27.94,82.56 K4_B4.C1
  Bottom 0.406: v50.8,38.75 50.8,41.29 49.53,42.56 41.27,42.56 38.73,45.1 38.73,50.81 v45.09,57.16 45.72,57.8 v45.72,69.23
REG_5V  (via drill 0.5, 0.6, 0.9)
  Top 0.254: 201.29,67.32 201.29,67 | RN1.6 RN1.5 232.66,61.21 232.66,61.73 232.28,62.12 v232.28,62.5
  Top 0.305: IC2.15 v66.04,53.99 66.67,53.99 69.85,50.81 69.85,47.64 | 175.9,53.99 177.16,55.26 177.8,55.26 178.44,55.89 | IC2.9 72.39,56.53 v71.12,55.26 | IC1.18 v175.9,53.35 | IC1.9 178.44,55.89 | 178.44,55.89 179.07,55.26 189.55,55.26 189.87,55.26 191.13,56.53 196.22,56.53 | 196.22,56.53 196.85,56.53 200.03,59.7 201.29,59.7 201.53,59.47 | 201.76,63.68 U$13.B2 | C1.1 196.3,56.44 196.22,56.53 | RNB1.6 243.67,27.15 243.21,26.68 243.21,24.14 243.84,23.51 255.02,23.51 v255.78,22.75
  Top 0.406: C2.1 C3.1 | C4.1 C1.1 | IC2.18 69.85,50.81 70.48,51.45 84.86,51.45 | C8.1 84.86,51.45 | 84.86,51.45 C5.1 84.86,45.96 85.09,45.73 89.85,45.73 90.17,46.05 90.17,46.37 | C6.1 C7.1 190.91,54.22 189.87,55.26 | 90.17,47.64 90.17,47.72 | 90.17,47.72 C3.1 | C3.1 90.17,47.96 90.17,47.72
  Top 0.61: v232.28,62.5 234.06,62.5 237.49,59.07 X18.2
  Top 0.813: H1.1 227.17,36.69 v226.69,36.21 | IC6.4 217.93,38.87 | 217.93,38.87 v217.81,38.75 | 217.93,38.87 214.86,38.87 C10.1
  Top 1.016: 95.25,45.73 90.49,45.73 90.17,46.05 | 90.17,46.37 90.17,47.64 | C24.+ 96.52,47 95.25,45.73 | C28.+ 96.52,44.46 95.25,45.73 | C1.1 196.3,48.18 197.1,47.38 201.17,47.38 201.93,46.62 C25.+ 201.93,36.21 200.66,34.94 183.51,34.94 183.2,35.25 | C26.+ 173.99,36.21 175.26,34.94 182.88,34.94 183.2,35.25 | 183.2,35.25 183.51,35.57 C27.+
  Top 1.27: 201.29,67 U$13.A2 U$13.B2 201.29,60.02 199.71,60.02 196.53,56.85 191.13,56.85 189.55,55.26 178.75,55.26 178.44,55.58 177.48,55.58 175.9,53.99 v175.9,53.35 | H1.1 235.68,35.42 v236.22,35.83
  Bottom 0.254: 256.54,21.6 258.44,21.6 259.71,22.87 259.71,43.19 260.35,43.83 260.35,58.43 259.71,59.07 v255.02,59.07
  Bottom 0.305: v175.9,53.35 144.78,53.35 144.15,53.99 76.2,53.99 75.56,53.35 74.3,53.35 73.66,53.99 v66.04,53.99 66.04,54.62 66.67,55.26 v71.12,55.26 | v255.78,22.75 255.78,22.36 256.54,21.6
  Bottom 0.61: FOR_NANO.5V 230.5,64.27 | 230.5,64.27 v232.28,62.5 | 230.5,64.27 230.5,64.15 229.87,63.51 218.44,63.51 217.17,62.24
  Bottom 0.813: v226.69,36.21 217.81,36.21 v217.81,38.75 216.53,40.02 216.53,50.81 217.81,52.08 217.81,61.61 217.17,62.24 v215.9,62.24
  Bottom 1.016: v255.02,59.07 X18.2 | C25.+ 201.93,40.02 203.2,38.75 v217.81,38.75
REG_12V  (via drill 0.5)
  Top 0.813: BRA2.+ 242.57,40.02 240.66,37.48 233.04,37.48 229.24,41.29 226.95,41.29 v222.76,41.41 IC6.7 | C9.1 214.76,51.32 215.9,50.18 217.17,50.18 217.81,49.54 v217.81,44.46
  Bottom 0.813: v217.81,44.46 217.81,42.56 218.95,41.41 v222.76,41.41
UNREG_12V  (via drill 0.6)
  Top 0.305: 130.18,52.72 R1.A
  Top 0.406: IC5.10 v49.53,38.75 | IC4.10 v165.1,62.56 | R8.A 103.5,52.72 | R15.A 107.31,52.72 | R6.A 111.12,52.72 | 114.94,52.72 R13.A | R4.A 118.75,52.72 | R3.A 122.56,52.72 | R2.A 126.36,52.72 | R16.A 103.5,52.72 | 103.5,52.72 107.31,52.72 | R7.A 107.31,52.72 | 107.31,52.72 111.12,52.72 | R14.A 111.12,52.72 | 111.12,52.72 114.94,52.72 | R5.A 114.94,52.72 | 114.94,52.72 118.75,52.72 | R12.A 118.75,52.72 | 118.75,52.72 122.56,52.72 | R11.A 122.56,52.72 | 122.56,52.72 126.36,52.72 | R10.A 126.36,52.72 | v18.41,52.72 R19.A | 22.23,52.72 R18.A | 26.04,52.72 R17.A | R20.A 14.61,52.72 | 14.61,52.72 v18.41,52.72 | v18.41,52.72 22.23,52.72 | 22.23,52.72 26.04,52.72 | R9.A 130.18,52.72 | 130.18,50.81 130.18,52.72 | 130.18,52.72 127.95,52.72 | 126.36,52.72 127.95,52.72 | 127.95,52.72 v127.95,49.54 | IC3.10 154.94,39.38 v154.9,38.81 | R21.A 26.04,52.72 | R22.A 22.23,52.72 | R23.A v18.41,52.72 | R24.A 14.61,52.72
  Top 2.54: BRA2.~@2 BRA2.~@1 246.97,34.94 248.22,36.7 | 248.22,36.7 U$6.TIP | X17.2 257.49,29.22 252.09,29.22 248.28,33.03 248.28,36.64 248.22,36.7
  Bottom 0.305: 14.61,71.77 13.34,71.77 12.7,71.13 12.7,53.99 13.97,52.72 v18.41,52.72
  Bottom 0.406: v165.1,62.56 165.1,71.13 164.47,71.77 | v127.95,49.54 127.95,33.67 | 144.84,33.99 145.16,33.67
  Bottom 0.813: v49.53,38.75 49.53,33.67
  Bottom 1.016: 144.84,33.99 154.9,33.99 v154.9,38.81 | 146.05,71.13 145.41,71.77 | 86.36,33.67 87,34.3 C22.+ C20.+ | C23.+ 144.78,71.77 | 87.63,71.77 C21.+ C19.+ | K4_B4.C2 19.68,82.56 19.05,81.93 19.05,72.4 18.41,71.77 | K3_B4.C2 34.92,82.56 34.29,81.93 34.29,72.4 33.66,71.77 | K2_B4.C2 50.16,82.56 49.53,81.93 49.53,71.77 | K1_B4.C2 65.41,82.56 64.77,81.93 64.77,71.77 | K8_B2.C2 104.14,82.56 103.5,81.93 103.5,72.4 104.14,71.77 | K7_B2.C2 119.38,82.56 118.75,81.93 118.75,72.4 118.11,71.77 | K6_B2.C2 134.62,82.56 133.99,81.93 133.99,71.77 | K5_B2.C2 149.86,82.56 149.22,81.93 149.22,72.4 148.59,71.77 | K4_B2.C2 188.59,82.56 187.96,81.93 187.96,71.77 | K3_B2.C2 203.84,82.56 203.2,81.93 203.2,71.77 | K2_B2.C2 219.07,82.56 218.44,81.93 218.44,73.04 217.81,72.4 218.44,71.77 219.07,71.77 219.71,72.4 227.97,72.4 229.24,73.67 229.24,81.93 229.87,82.56 K1_B2.C2 234.31,82.56 | K1_B1.C2 242.57,22.87 243.21,23.51 243.21,33.67 244.43,33.67 | K2_B1.C2 227.33,22.87 227.97,23.51 227.97,33.67 | K3_B1.C2 212.09,22.87 212.72,23.51 212.72,33.03 213.36,33.67 | K4_B1.C2 196.85,22.87 197.49,23.51 197.49,33.67 | K5_B1.C2 158.12,22.87 158.75,23.51 158.75,33.67 | K6_B1.C2 142.88,22.87 143.51,23.51 143.51,33.67 | K7_B1.C2 127.64,22.87 128.27,23.51 128.27,33.03 128.91,33.67 | K8_B1.C2 112.39,22.87 113.03,23.51 113.03,33.67 | K4_B3.C2 27.94,22.87 28.57,23.51 28.57,33.03 27.94,33.67 | K3_B3.C2 43.18,22.87 43.81,23.51 43.81,33.67 | K2_B3.C2 58.42,22.87 59.05,23.51 59.05,33.67 | K1_B3.C2 73.66,22.87 74.3,23.51 74.3,33.67
  Bottom 2.54: 218.44,71.77 203.2,71.77 187.96,71.77 164.47,71.77 148.59,71.77 145.41,71.77 144.78,71.77 133.99,71.77 118.11,71.77 104.14,71.77 87.63,71.77 64.77,71.77 49.53,71.77 33.66,71.77 18.41,71.77 14.61,71.77 12.7,71.77 12.7,71.13 12.7,33.67 27.94,33.67 43.81,33.67 49.53,33.67 59.05,33.67 74.3,33.67 86.36,33.67 113.03,33.67 127.95,33.67 128.91,33.67 143.51,33.67 145.16,33.67 158.75,33.67 197.49,33.67 213.36,33.67 227.97,33.67 243.21,33.67 248.28,33.67 247.9,33.29 248.03,33.29 252.09,29.22 257.49,29.22 X17.2

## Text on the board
tNames: Bank 3 | NC | COM | NO | NC | COM | NO | NC | COM | NO | NC | COM | NO | NC | COM | NO | NC | COM | NO | NC | COM | NO | NC | COM | NO | NC | COM | NO | NC | COM | NO | NC | COM | NO | NC | COM | NO | 8 | 5 | 8 | 5 | 4 | 1 | REV.A | ANSIO8R24G5V1 | NC | COM | NO | NC | COM | NO | NC | COM | NO | NC | COM | NO | NC | COM | NO | NC | COM | NO | NC | COM | NO | NC | COM | NO | NC | COM | NO | NC | COM | NO | NC | COM | NO | NC | COM | NO | 1 | Bank 2 | MCP23017 | GPB0 | GND | GPB1 | Address: | GPB2 | A1 | GND | A2 | GND | 2016 ControlEverything.com | +5V | SC | GPB3 | SDA | SCL | GPB4 | GND | Address A0=1 | Address A0=0 | GPB5 | GPB6 | GND | GPB7 | 8 | Bank 1 | NO | COM | NC | NO | COM | NC | NO | COM | NC | NO | COM | NC | NO | COM | NC | NO | COM | NC | NO | COM | NC | NO | COM | NC | NO | COM | NC | NO | COM | NC | NO | COM | NC | NO | COM | NC | 4 | 1 | 8 | 5 | 4 | 1 | 12V DC / Power / Supply | 12V DC / Power / Supply | 12V DC / Power / Supply | NO | COM | NC | NO | COM | NC | NO | COM | NC | NO | COM | NC | NO | COM | NC | NO | COM | NC | NO | COM | NC | NO | COM | NC | NO | COM | NC | NO | COM | NC | NO | COM | NC | NO | COM | NC | Bank 3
